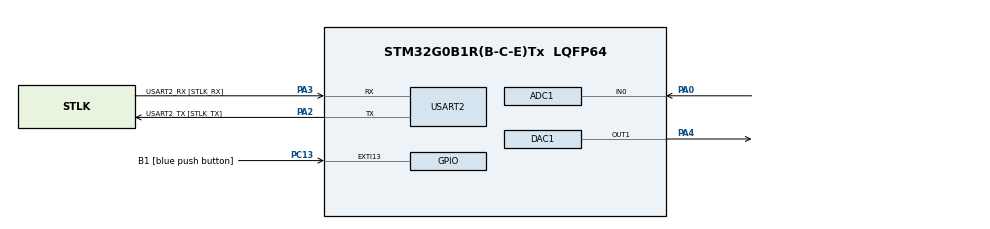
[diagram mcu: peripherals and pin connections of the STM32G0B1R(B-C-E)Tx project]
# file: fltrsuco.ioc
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ADC1.Channel-0\#ChannelRegularConversion=ADC_CHANNEL_0
ADC1.DMAContinuousRequests=ENABLE
ADC1.ExternalTrigConv=ADC_EXTERNALTRIG_T3_TRGO
ADC1.NbrOfConversion=1
ADC1.NbrOfConversionFlag=1
ADC1.Rank-0\#ChannelRegularConversion=1
ADC1.SamplingTime-0\#ChannelRegularConversion=ADC_SAMPLINGTIME_COMMON_1
ADC1.SamplingTimeCommon1=ADC_SAMPLETIME_39CYCLES_5
ADC1.SelectedChannel=ADC_CHANNEL_0
ADC1.master=1
DAC1.DAC_Channel-DAC_OUT1=DAC_CHANNEL_1
DAC1.DAC_Trigger-DAC_OUT1=DAC_TRIGGER_T3_TRGO
Dma.ADC1.1.Direction=DMA_PERIPH_TO_MEMORY
Dma.ADC1.1.EventEnable=DISABLE
Dma.ADC1.1.Instance=DMA1_Channel2
Dma.ADC1.1.MemDataAlignment=DMA_MDATAALIGN_HALFWORD
Dma.ADC1.1.MemInc=DMA_MINC_ENABLE
Dma.ADC1.1.Mode=DMA_CIRCULAR
Dma.ADC1.1.PeriphDataAlignment=DMA_PDATAALIGN_HALFWORD
Dma.ADC1.1.PeriphInc=DMA_PINC_DISABLE
Dma.ADC1.1.Polarity=HAL_DMAMUX_REQ_GEN_RISING
Dma.ADC1.1.Priority=DMA_PRIORITY_LOW
Dma.ADC1.1.RequestNumber=1
Dma.ADC1.1.SignalID=NONE
Dma.ADC1.1.SyncEnable=DISABLE
Dma.ADC1.1.SyncPolarity=HAL_DMAMUX_SYNC_NO_EVENT
Dma.ADC1.1.SyncRequestNumber=1
Dma.ADC1.1.SyncSignalID=NONE
Dma.DAC1_CH1.2.Direction=DMA_MEMORY_TO_PERIPH
Dma.DAC1_CH1.2.EventEnable=DISABLE
Dma.DAC1_CH1.2.Instance=DMA1_Channel3
Dma.DAC1_CH1.2.MemDataAlignment=DMA_MDATAALIGN_HALFWORD
Dma.DAC1_CH1.2.MemInc=DMA_MINC_ENABLE
Dma.DAC1_CH1.2.Mode=DMA_CIRCULAR
Dma.DAC1_CH1.2.PeriphDataAlignment=DMA_PDATAALIGN_HALFWORD
Dma.DAC1_CH1.2.PeriphInc=DMA_PINC_DISABLE
Dma.DAC1_CH1.2.Polarity=HAL_DMAMUX_REQ_GEN_RISING
Dma.DAC1_CH1.2.Priority=DMA_PRIORITY_HIGH
Dma.DAC1_CH1.2.RequestNumber=1
Dma.DAC1_CH1.2.SignalID=NONE
Dma.DAC1_CH1.2.SyncEnable=DISABLE
Dma.DAC1_CH1.2.SyncPolarity=HAL_DMAMUX_SYNC_NO_EVENT
Dma.DAC1_CH1.2.SyncRequestNumber=1
Dma.DAC1_CH1.2.SyncSignalID=NONE
Dma.Request0=USART2_TX
Dma.Request1=ADC1
Dma.Request2=DAC1_CH1
Dma.USART2_TX.0.Direction=DMA_MEMORY_TO_PERIPH
Dma.USART2_TX.0.EventEnable=DISABLE
Dma.USART2_TX.0.Instance=DMA1_Channel1
Dma.USART2_TX.0.MemDataAlignment=DMA_MDATAALIGN_BYTE
Dma.USART2_TX.0.MemInc=DMA_MINC_ENABLE
Dma.USART2_TX.0.Mode=DMA_NORMAL
Dma.USART2_TX.0.PeriphDataAlignment=DMA_PDATAALIGN_BYTE
Dma.USART2_TX.0.PeriphInc=DMA_PINC_DISABLE
Dma.USART2_TX.0.Polarity=HAL_DMAMUX_REQ_GEN_RISING
Dma.USART2_TX.0.Priority=DMA_PRIORITY_LOW
Dma.USART2_TX.0.RequestNumber=1
Dma.USART2_TX.0.SignalID=NONE
Dma.USART2_TX.0.SyncEnable=DISABLE
Dma.USART2_TX.0.SyncPolarity=HAL_DMAMUX_SYNC_NO_EVENT
Dma.USART2_TX.0.SyncRequestNumber=1
Dma.USART2_TX.0.SyncSignalID=NONE
Mcu.Family=STM32G0
Mcu.Name=STM32G0B1R(B-C-E)Tx
Mcu.Package=LQFP64
NVIC.ADC1_COMP_IRQn=true\:0\:0\:false\:false\:true\:true\:true\:true
NVIC.DMA1_Channel1_IRQn=true\:0\:0\:false\:false\:true\:false\:true\:true
NVIC.DMA1_Channel2_3_IRQn=true\:0\:0\:false\:false\:true\:false\:true\:true
NVIC.USART2_LPUART2_IRQn=true\:1\:0\:true\:false\:true\:true\:true\:true
PA0.Mode=IN0
PA0.Signal=ADC1_IN0
PA13.GPIO_Label=TMS
PA13.Mode=Serial_Wire
PA13.Signal=SYS_SWDIO
PA14-BOOT0.GPIO_Label=TCK
PA14-BOOT0.Mode=Serial_Wire
PA14-BOOT0.Signal=SYS_SWCLK
PA2.GPIO_Label=USART2_TX [STLK_TX]
PA2.Mode=Asynchronous
PA2.Signal=USART2_TX
PA3.GPIO_Label=USART2_RX [STLK_RX]
PA3.Mode=Asynchronous
PA3.Signal=USART2_RX
PA4.Signal=COMP_DAC11_group
PC13.GPIO_Label=B1 [blue push button]
PC13.Signal=GPXTI13
PC14-OSC32_IN\ (PC14).Mode=LSE-External-Oscillator
PC14-OSC32_IN\ (PC14).Signal=RCC_OSC32_IN
PC15-OSC32_OUT\ (PC15).Mode=LSE-External-Oscillator
PC15-OSC32_OUT\ (PC15).Signal=RCC_OSC32_OUT
PF0-OSC_IN\ (PF0).GPIO_Label=MCO
PF0-OSC_IN\ (PF0).Mode=HSE-External-Clock-Source
PF0-OSC_IN\ (PF0).Signal=RCC_OSC_IN
ProjectManager.HeapSize=0x200
ProjectManager.StackSize=0x400
ProjectManager.TargetToolchain=STM32CubeIDE
RCC.ADCFreq_Value=64000000
RCC.AHBFreq_Value=64000000
RCC.CortexFreq_Value=64000000
RCC.EXTERNAL_CLOCK_VALUE=12288000
RCC.HCLKFreq_Value=64000000
RCC.HSE_VALUE=8000000
RCC.HSI48_VALUE=48000000
RCC.HSI_VALUE=16000000
RCC.SYSCLKFreq_VALUE=64000000
RCC.SYSCLKSource=RCC_SYSCLKSOURCE_PLLCLK
RCC.USBFreq_Value=48000000
RCC.VCOOutputFreq_Value=128000000
SH.COMP_DAC11_group.0=DAC1_OUT1,DAC_OUT1
TIM3.Period=639
TIM3.Prescaler=0
TIM3.TIM_MasterOutputTrigger=TIM_TRGO_UPDATE
USART2.VirtualMode-Asynchronous=VM_ASYNC
VP_SYS_VS_DBSignals.Mode=DisableDeadBatterySignals
VP_TIM3_VS_ClockSourceINT.Mode=Internal
board=NUCLEO-G0B1RE

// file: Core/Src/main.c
/* USER CODE BEGIN Header */
/**
  ******************************************************************************
  * @file           : main.c
  * @brief          : Main program body
  ******************************************************************************
  * @attention
  *
  * Copyright (c) 2026 STMicroelectronics.
  * All rights reserved.
  *
  * This software is licensed under terms that can be found in the LICENSE file
  * in the root directory of this software component.
  * If no LICENSE file comes with this software, it is provided AS-IS.
  *
  ******************************************************************************
  */
/* USER CODE END Header */
#include "main.h"

ADC_HandleTypeDef hadc1;
DMA_HandleTypeDef hdma_adc1;

DAC_HandleTypeDef hdac1;
DMA_HandleTypeDef hdma_dac1_ch1;

TIM_HandleTypeDef htim3;

UART_HandleTypeDef huart2;
DMA_HandleTypeDef hdma_usart2_tx;

/* USER CODE BEGIN PV */
#define QNT_AMOSTRAS 256
uint16_t amostras[QNT_AMOSTRAS];
uint16_t saida_dac[QNT_AMOSTRAS0];
/* USER CODE END PV */

void SystemClock_Config(void);
static void MX_GPIO_Init(void);
static void MX_DMA_Init(void);
static void MX_ADC1_Init(void);
static void MX_TIM3_Init(void);
static void MX_USART2_UART_Init(void);
static void MX_DAC1_Init(void);

int main(void)
{

  /* MCU Configuration--------------------------------------------------------*/

  /* Reset of all peripherals, Initializes the Flash interface and the Systick. */
  HAL_Init();

  /* Configure the system clock */
  SystemClock_Config();

  /* Initialize all configured peripherals */
  MX_GPIO_Init();
  MX_DMA_Init();
  MX_ADC1_Init();
  MX_TIM3_Init();
  MX_USART2_UART_Init();
  MX_DAC1_Init();
  /* USER CODE BEGIN 2 */
  HAL_DAC_Start_DMA(&hdac1, DAC_CHANNEL_1, saida_dac, QNT_AMOSTRAS, DAC_ALIGN_12B_L);
  HAL_ADC_Start_DMA(&hadc1, (uint32_t *)amostras, QNT_AMOSTRAS);
  HAL_TIM_Base_Start(&htim3);

  /* USER CODE END 2 */

  /* Infinite loop */
  while (1)
  {

  }
}

void SystemClock_Config(void)
{
  RCC_OscInitTypeDef RCC_OscInitStruct = {0};
  RCC_ClkInitTypeDef RCC_ClkInitStruct = {0};

  /** Configure the main internal regulator output voltage
  */
  HAL_PWREx_ControlVoltageScaling(PWR_REGULATOR_VOLTAGE_SCALE1);

  /** Initializes the RCC Oscillators according to the specified parameters
  * in the RCC_OscInitTypeDef structure.
  */
  RCC_OscInitStruct.OscillatorType = RCC_OSCILLATORTYPE_HSI;
  RCC_OscInitStruct.HSIState = RCC_HSI_ON;
  RCC_OscInitStruct.HSIDiv = RCC_HSI_DIV1;
  RCC_OscInitStruct.HSICalibrationValue = RCC_HSICALIBRATION_DEFAULT;
  RCC_OscInitStruct.PLL.PLLState = RCC_PLL_NONE;
  if (HAL_RCC_OscConfig(&RCC_OscInitStruct) != HAL_OK)
  {
    Error_Handler();
  }

  /** Initializes the CPU, AHB and APB buses clocks
  */
  RCC_ClkInitStruct.ClockType = RCC_CLOCKTYPE_HCLK|RCC_CLOCKTYPE_SYSCLK
                              |RCC_CLOCKTYPE_PCLK1;
  RCC_ClkInitStruct.SYSCLKSource = RCC_SYSCLKSOURCE_HSI;
  RCC_ClkInitStruct.AHBCLKDivider = RCC_SYSCLK_DIV1;
  RCC_ClkInitStruct.APB1CLKDivider = RCC_HCLK_DIV1;

  if (HAL_RCC_ClockConfig(&RCC_ClkInitStruct, FLASH_LATENCY_0) != HAL_OK)
  {
    Error_Handler();
  }
}

static void MX_ADC1_Init(void)
{

  ADC_ChannelConfTypeDef sConfig = {0};

  /** Configure the global features of the ADC (Clock, Resolution, Data Alignment and number of conversion)
  */
  hadc1.Instance = ADC1;
  hadc1.Init.ClockPrescaler = ADC_CLOCK_SYNC_PCLK_DIV2;
  hadc1.Init.Resolution = ADC_RESOLUTION_12B;
  hadc1.Init.DataAlign = ADC_DATAALIGN_RIGHT;
  hadc1.Init.ScanConvMode = ADC_SCAN_DISABLE;
  hadc1.Init.EOCSelection = ADC_EOC_SINGLE_CONV;
  hadc1.Init.LowPowerAutoWait = DISABLE;
  hadc1.Init.LowPowerAutoPowerOff = DISABLE;
  hadc1.Init.ContinuousConvMode = DISABLE;
  hadc1.Init.NbrOfConversion = 1;
  hadc1.Init.DiscontinuousConvMode = DISABLE;
  hadc1.Init.ExternalTrigConv = ADC_EXTERNALTRIG_T3_TRGO;
  hadc1.Init.ExternalTrigConvEdge = ADC_EXTERNALTRIGCONVEDGE_RISING;
  hadc1.Init.DMAContinuousRequests = ENABLE;
  hadc1.Init.Overrun = ADC_OVR_DATA_PRESERVED;
  hadc1.Init.SamplingTimeCommon1 = ADC_SAMPLETIME_1CYCLE_5;
  hadc1.Init.SamplingTimeCommon2 = ADC_SAMPLETIME_1CYCLE_5;
  hadc1.Init.OversamplingMode = DISABLE;
  hadc1.Init.TriggerFrequencyMode = ADC_TRIGGER_FREQ_HIGH;
  if (HAL_ADC_Init(&hadc1) != HAL_OK)
  {
    Error_Handler();
  }

  /** Configure Regular Channel
  */
  sConfig.Channel = ADC_CHANNEL_0;
  sConfig.Rank = ADC_REGULAR_RANK_1;
  sConfig.SamplingTime = ADC_SAMPLINGTIME_COMMON_1;
  if (HAL_ADC_ConfigChannel(&hadc1, &sConfig) != HAL_OK)
  {
    Error_Handler();
  }

}

static void MX_DAC1_Init(void)
{

  DAC_ChannelConfTypeDef sConfig = {0};

  /** DAC Initialization
  */
  hdac1.Instance = DAC1;
  if (HAL_DAC_Init(&hdac1) != HAL_OK)
  {
    Error_Handler();
  }

  /** DAC channel OUT1 config
  */
  sConfig.DAC_SampleAndHold = DAC_SAMPLEANDHOLD_DISABLE;
  sConfig.DAC_Trigger = DAC_TRIGGER_T3_TRGO;
  sConfig.DAC_OutputBuffer = DAC_OUTPUTBUFFER_ENABLE;
  sConfig.DAC_ConnectOnChipPeripheral = DAC_CHIPCONNECT_DISABLE;
  sConfig.DAC_UserTrimming = DAC_TRIMMING_FACTORY;
  if (HAL_DAC_ConfigChannel(&hdac1, &sConfig, DAC_CHANNEL_1) != HAL_OK)
  {
    Error_Handler();
  }

}

static void MX_TIM3_Init(void)
{

  TIM_ClockConfigTypeDef sClockSourceConfig = {0};
  TIM_MasterConfigTypeDef sMasterConfig = {0};

  htim3.Instance = TIM3;
  htim3.Init.Prescaler = 0;
  htim3.Init.CounterMode = TIM_COUNTERMODE_UP;
  htim3.Init.Period = 363;
  htim3.Init.ClockDivision = TIM_CLOCKDIVISION_DIV1;
  htim3.Init.AutoReloadPreload = TIM_AUTORELOAD_PRELOAD_DISABLE;
  if (HAL_TIM_Base_Init(&htim3) != HAL_OK)
  {
    Error_Handler();
  }
  sClockSourceConfig.ClockSource = TIM_CLOCKSOURCE_INTERNAL;
  if (HAL_TIM_ConfigClockSource(&htim3, &sClockSourceConfig) != HAL_OK)
  {
    Error_Handler();
  }
  sMasterConfig.MasterOutputTrigger = TIM_TRGO_UPDATE;
  sMasterConfig.MasterSlaveMode = TIM_MASTERSLAVEMODE_DISABLE;
  if (HAL_TIMEx_MasterConfigSynchronization(&htim3, &sMasterConfig) != HAL_OK)
  {
    Error_Handler();
  }

}

static void MX_USART2_UART_Init(void)
{

  huart2.Instance = USART2;
  huart2.Init.BaudRate = 115200;
  huart2.Init.WordLength = UART_WORDLENGTH_8B;
  huart2.Init.StopBits = UART_STOPBITS_1;
  huart2.Init.Parity = UART_PARITY_NONE;
  huart2.Init.Mode = UART_MODE_TX_RX;
  huart2.Init.HwFlowCtl = UART_HWCONTROL_NONE;
  huart2.Init.OverSampling = UART_OVERSAMPLING_16;
  huart2.Init.OneBitSampling = UART_ONE_BIT_SAMPLE_DISABLE;
  huart2.Init.ClockPrescaler = UART_PRESCALER_DIV1;
  huart2.AdvancedInit.AdvFeatureInit = UART_ADVFEATURE_NO_INIT;
  if (HAL_UART_Init(&huart2) != HAL_OK)
  {
    Error_Handler();
  }
  if (HAL_UARTEx_SetTxFifoThreshold(&huart2, UART_TXFIFO_THRESHOLD_1_8) != HAL_OK)
  {
    Error_Handler();
  }
  if (HAL_UARTEx_SetRxFifoThreshold(&huart2, UART_RXFIFO_THRESHOLD_1_8) != HAL_OK)
  {
    Error_Handler();
  }
  if (HAL_UARTEx_DisableFifoMode(&huart2) != HAL_OK)
  {
    Error_Handler();
  }

}

static void MX_DMA_Init(void)
{

  /* DMA controller clock enable */
  __HAL_RCC_DMA1_CLK_ENABLE();

  /* DMA interrupt init */
  /* DMA1_Channel1_IRQn interrupt configuration */
  HAL_NVIC_SetPriority(DMA1_Channel1_IRQn, 0, 0);
  HAL_NVIC_EnableIRQ(DMA1_Channel1_IRQn);
  /* DMA1_Channel2_3_IRQn interrupt configuration */
  HAL_NVIC_SetPriority(DMA1_Channel2_3_IRQn, 0, 0);
  HAL_NVIC_EnableIRQ(DMA1_Channel2_3_IRQn);

}

static void MX_GPIO_Init(void)
{
  GPIO_InitTypeDef GPIO_InitStruct = {0};

  /* GPIO Ports Clock Enable */
  __HAL_RCC_GPIOC_CLK_ENABLE();
  __HAL_RCC_GPIOF_CLK_ENABLE();
  __HAL_RCC_GPIOA_CLK_ENABLE();

  /*Configure GPIO pin : B1_Pin */
  GPIO_InitStruct.Pin = B1_Pin;
  GPIO_InitStruct.Mode = GPIO_MODE_IT_RISING;
  GPIO_InitStruct.Pull = GPIO_NOPULL;
  HAL_GPIO_Init(B1_GPIO_Port, &GPIO_InitStruct);

}

void Error_Handler(void)
{
  __disable_irq();
  while (1)
  {
  }
}
